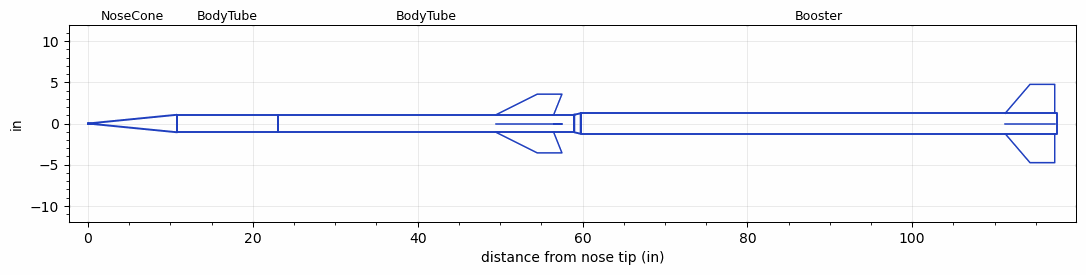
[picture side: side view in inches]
<RASAeroDocument>
 <FileVersion>2</FileVersion>
 <RocketDesign>
  <NoseCone>
   <Length>10.8</Length>
   <Diameter>2.125</Diameter>
   <Shape>Conical</Shape>
   <BluntRadius>0.0625</BluntRadius>
   <Location>0</Location>
  </NoseCone>
  <BodyTube>
   <Length>12.2</Length>
   <Diameter>2.125</Diameter>
   <Location>10.8</Location>
  </BodyTube>
  <BodyTube>
   <Length>36</Length>
   <Diameter>2.125</Diameter>
   <Location>23</Location>
   <Fin>
    <Count>4</Count>
    <Chord>7</Chord>
    <Span>2.5</Span>
    <SweepDistance>5</SweepDistance>
    <TipChord>3</TipChord>
    <Thickness>0.125</Thickness>
    <LERadius>0.01</LERadius>
    <Location>9.5</Location>
    <AirfoilSection>Hexagonal</AirfoilSection>
    <FX1>0.5</FX1>
    <FX3>0.5</FX3>
   </Fin>
  </BodyTube>
  <Booster>
   <Length>57.765</Length>
   <Diameter>2.5</Diameter>
   <InsideDiameter>2.125</InsideDiameter>
   <RailGuideDiameter>0.625</RailGuideDiameter>
   <RailGuideHeight>0.4</RailGuideHeight>
   <Location>59</Location>
   <ShoulderLength>0.775</ShoulderLength>
   <Fin>
    <Count>4</Count>
    <Chord>6</Chord>
    <Span>3.5</Span>
    <SweepDistance>3</SweepDistance>
    <TipChord>3</TipChord>
    <Thickness>0.375</Thickness>
    <LERadius>0.01</LERadius>
    <Location>6.25</Location>
    <AirfoilSection>Hexagonal</AirfoilSection>
    <FX1>0.5</FX1>
    <FX3>0.5</FX3>
   </Fin>
  </Booster>
  <Surface>Camouflage Paint</Surface>
  <ModifiedBarrowman>True</ModifiedBarrowman>
  <Turbulence>True</Turbulence>
  <UseBooster1>False</UseBooster1>
  <UseBooster2>False</UseBooster2>
 </RocketDesign>
 <LaunchSite>
  <Altitude>4000</Altitude>
  <Pressure>0</Pressure>
  <RodAngle>2</RodAngle>
  <RodLength>20</RodLength>
  <Temperature>75</Temperature>
  <WindSpeed>7</WindSpeed>
 </LaunchSite>
 <Recovery>
  <Altitude1>1000</Altitude1>
  <Altitude2>1000</Altitude2>
  <DeviceType1>None</DeviceType1>
  <DeviceType2>None</DeviceType2>
  <Event1>False</Event1>
  <Event2>False</Event2>
  <Size1>1</Size1>
  <Size2>1</Size2>
  <EventType1>None</EventType1>
  <EventType2>None</EventType2>
  <CD1>1.33</CD1>
  <CD2>1.33</CD2>
 </Recovery>
 <SimulationList>
  <Simulation>
   <SustainerEngine>L2342  (BPS)</SustainerEngine>
   <SustainerLaunchWt>10</SustainerLaunchWt>
   <SustainerNozzleDiameter>2</SustainerNozzleDiameter>
   <SustainerCG>36</SustainerCG>
   <SustainerIgnitionDelay>8</SustainerIgnitionDelay>
   <Booster1Engine>N2363  (bps)</Booster1Engine>
   <Booster1LaunchWt>27</Booster1LaunchWt>
   <Booster1SeparationDelay>0</Booster1SeparationDelay>
   <Booster1IgnitionDelay>0</Booster1IgnitionDelay>
   <Booster1CG>70</Booster1CG>
   <Booster1NozzleDiameter>2</Booster1NozzleDiameter>
   <IncludeBooster1>True</IncludeBooster1>
   <Booster2Delay>0</Booster2Delay>
   <IncludeBooster2>False</IncludeBooster2>
   <TimetoApogee>127.5879</TimetoApogee>
   <MaxAltitude>243344.3</MaxAltitude>
   <MaxVelocity>5554.188</MaxVelocity>
  </Simulation>
  <Simulation>
   <SustainerEngine>L2342  (BPS)</SustainerEngine>
   <SustainerLaunchWt>10</SustainerLaunchWt>
   <SustainerNozzleDiameter>2</SustainerNozzleDiameter>
   <SustainerCG>36</SustainerCG>
   <SustainerIgnitionDelay>2</SustainerIgnitionDelay>
   <Booster1Engine>N2363  (bps)</Booster1Engine>
   <Booster1LaunchWt>27</Booster1LaunchWt>
   <Booster1SeparationDelay>0</Booster1SeparationDelay>
   <Booster1IgnitionDelay>0</Booster1IgnitionDelay>
   <Booster1CG>70</Booster1CG>
   <Booster1NozzleDiameter>2</Booster1NozzleDiameter>
   <IncludeBooster1>True</IncludeBooster1>
   <Booster2Delay>0</Booster2Delay>
   <IncludeBooster2>False</IncludeBooster2>
   <TimetoApogee>106.8335</TimetoApogee>
   <MaxAltitude>189701.6</MaxAltitude>
   <MaxVelocity>5890.19</MaxVelocity>
  </Simulation>
 </SimulationList>
</RASAeroDocument>
